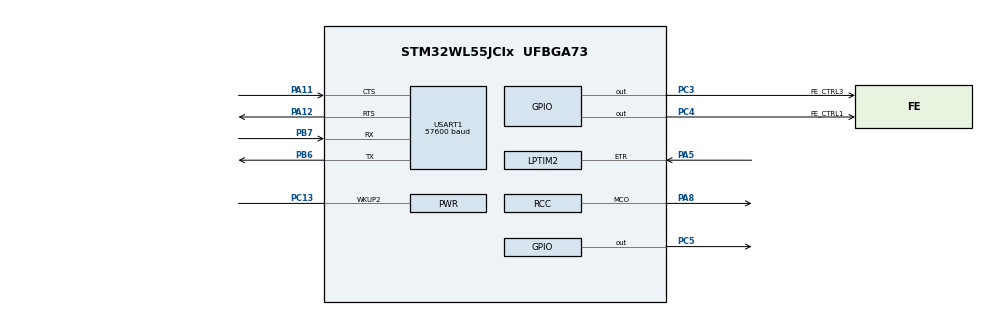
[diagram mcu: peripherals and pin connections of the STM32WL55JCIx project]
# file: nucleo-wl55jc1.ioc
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AES.KeySize=CRYP_KEYSIZE_128B
AES.pKey=DA123456 BE13579B FF3CC201 0F66CAED
Dma.MEMTOMEM.2.Channel_PRIV_NPRIV=DMA_CHANNEL_NPRIV_DISABLE
Dma.MEMTOMEM.2.Direction=DMA_MEMORY_TO_MEMORY
Dma.MEMTOMEM.2.EventEnable=DISABLE
Dma.MEMTOMEM.2.Instance=DMA1_Channel1
Dma.MEMTOMEM.2.MemDataAlignment=DMA_MDATAALIGN_BYTE
Dma.MEMTOMEM.2.MemInc=DMA_MINC_ENABLE
Dma.MEMTOMEM.2.Mode=DMA_NORMAL
Dma.MEMTOMEM.2.PeriphDataAlignment=DMA_PDATAALIGN_BYTE
Dma.MEMTOMEM.2.PeriphInc=DMA_PINC_ENABLE
Dma.MEMTOMEM.2.Polarity=HAL_DMAMUX_REQ_GEN_RISING
Dma.MEMTOMEM.2.Priority=DMA_PRIORITY_MEDIUM
Dma.MEMTOMEM.2.RequestNumber=1
Dma.MEMTOMEM.2.SignalID=NONE
Dma.MEMTOMEM.2.SyncEnable=DISABLE
Dma.MEMTOMEM.2.SyncPolarity=HAL_DMAMUX_SYNC_NO_EVENT
Dma.MEMTOMEM.2.SyncRequestNumber=1
Dma.MEMTOMEM.2.SyncSignalID=NONE
Dma.MEMTOMEM.3.Channel_PRIV_NPRIV=DMA_CHANNEL_NPRIV_DISABLE
Dma.MEMTOMEM.3.Direction=DMA_MEMORY_TO_MEMORY
Dma.MEMTOMEM.3.EventEnable=DISABLE
Dma.MEMTOMEM.3.Instance=DMA1_Channel2
Dma.MEMTOMEM.3.MemDataAlignment=DMA_MDATAALIGN_BYTE
Dma.MEMTOMEM.3.MemInc=DMA_MINC_ENABLE
Dma.MEMTOMEM.3.Mode=DMA_NORMAL
Dma.MEMTOMEM.3.PeriphDataAlignment=DMA_PDATAALIGN_BYTE
Dma.MEMTOMEM.3.PeriphInc=DMA_PINC_ENABLE
Dma.MEMTOMEM.3.Polarity=HAL_DMAMUX_REQ_GEN_RISING
Dma.MEMTOMEM.3.Priority=DMA_PRIORITY_MEDIUM
Dma.MEMTOMEM.3.RequestNumber=1
Dma.MEMTOMEM.3.SignalID=NONE
Dma.MEMTOMEM.3.SyncEnable=DISABLE
Dma.MEMTOMEM.3.SyncPolarity=HAL_DMAMUX_SYNC_NO_EVENT
Dma.MEMTOMEM.3.SyncRequestNumber=1
Dma.MEMTOMEM.3.SyncSignalID=NONE
Dma.MEMTOMEM.4.Channel_PRIV_NPRIV=DMA_CHANNEL_NPRIV_DISABLE
Dma.MEMTOMEM.4.Direction=DMA_MEMORY_TO_MEMORY
Dma.MEMTOMEM.4.EventEnable=DISABLE
Dma.MEMTOMEM.4.Instance=DMA1_Channel3
Dma.MEMTOMEM.4.MemDataAlignment=DMA_MDATAALIGN_BYTE
Dma.MEMTOMEM.4.MemInc=DMA_MINC_ENABLE
Dma.MEMTOMEM.4.Mode=DMA_NORMAL
Dma.MEMTOMEM.4.PeriphDataAlignment=DMA_PDATAALIGN_BYTE
Dma.MEMTOMEM.4.PeriphInc=DMA_PINC_ENABLE
Dma.MEMTOMEM.4.Polarity=HAL_DMAMUX_REQ_GEN_RISING
Dma.MEMTOMEM.4.Priority=DMA_PRIORITY_LOW
Dma.MEMTOMEM.4.RequestNumber=1
Dma.MEMTOMEM.4.SignalID=NONE
Dma.MEMTOMEM.4.SyncEnable=DISABLE
Dma.MEMTOMEM.4.SyncPolarity=HAL_DMAMUX_SYNC_NO_EVENT
Dma.MEMTOMEM.4.SyncRequestNumber=1
Dma.MEMTOMEM.4.SyncSignalID=NONE
Dma.MEMTOMEM.5.Channel_PRIV_NPRIV=DMA_CHANNEL_NPRIV_DISABLE
Dma.MEMTOMEM.5.Direction=DMA_MEMORY_TO_MEMORY
Dma.MEMTOMEM.5.EventEnable=DISABLE
Dma.MEMTOMEM.5.Instance=DMA1_Channel4
Dma.MEMTOMEM.5.MemDataAlignment=DMA_MDATAALIGN_BYTE
Dma.MEMTOMEM.5.MemInc=DMA_MINC_ENABLE
Dma.MEMTOMEM.5.Mode=DMA_NORMAL
Dma.MEMTOMEM.5.PeriphDataAlignment=DMA_PDATAALIGN_BYTE
Dma.MEMTOMEM.5.PeriphInc=DMA_PINC_ENABLE
Dma.MEMTOMEM.5.Polarity=HAL_DMAMUX_REQ_GEN_RISING
Dma.MEMTOMEM.5.Priority=DMA_PRIORITY_LOW
Dma.MEMTOMEM.5.RequestNumber=1
Dma.MEMTOMEM.5.SignalID=NONE
Dma.MEMTOMEM.5.SyncEnable=DISABLE
Dma.MEMTOMEM.5.SyncPolarity=HAL_DMAMUX_SYNC_NO_EVENT
Dma.MEMTOMEM.5.SyncRequestNumber=1
Dma.MEMTOMEM.5.SyncSignalID=NONE
Dma.Request0=USART1_RX
Dma.Request1=USART1_TX
Dma.Request2=MEMTOMEM
Dma.Request3=MEMTOMEM
Dma.Request4=MEMTOMEM
Dma.Request5=MEMTOMEM
Dma.USART1_RX.0.Channel_PRIV_NPRIV=DMA_CHANNEL_NPRIV_DISABLE
Dma.USART1_RX.0.Direction=DMA_PERIPH_TO_MEMORY
Dma.USART1_RX.0.EventEnable=ENABLE
Dma.USART1_RX.0.Instance=DMA1_Channel5
Dma.USART1_RX.0.MemDataAlignment=DMA_MDATAALIGN_BYTE
Dma.USART1_RX.0.MemInc=DMA_MINC_ENABLE
Dma.USART1_RX.0.Mode=DMA_NORMAL
Dma.USART1_RX.0.PeriphDataAlignment=DMA_PDATAALIGN_BYTE
Dma.USART1_RX.0.PeriphInc=DMA_PINC_DISABLE
Dma.USART1_RX.0.Polarity=HAL_DMAMUX_REQ_GEN_RISING
Dma.USART1_RX.0.Priority=DMA_PRIORITY_LOW
Dma.USART1_RX.0.RequestNumber=1
Dma.USART1_RX.0.SignalID=NONE
Dma.USART1_RX.0.SyncEnable=DISABLE
Dma.USART1_RX.0.SyncPolarity=HAL_DMAMUX_SYNC_NO_EVENT
Dma.USART1_RX.0.SyncRequestNumber=1
Dma.USART1_RX.0.SyncSignalID=NONE
Dma.USART1_TX.1.Channel_PRIV_NPRIV=DMA_CHANNEL_NPRIV_DISABLE
Dma.USART1_TX.1.Direction=DMA_MEMORY_TO_PERIPH
Dma.USART1_TX.1.EventEnable=ENABLE
Dma.USART1_TX.1.Instance=DMA1_Channel6
Dma.USART1_TX.1.MemDataAlignment=DMA_MDATAALIGN_BYTE
Dma.USART1_TX.1.MemInc=DMA_MINC_ENABLE
Dma.USART1_TX.1.Mode=DMA_NORMAL
Dma.USART1_TX.1.PeriphDataAlignment=DMA_PDATAALIGN_BYTE
Dma.USART1_TX.1.PeriphInc=DMA_PINC_DISABLE
Dma.USART1_TX.1.Polarity=HAL_DMAMUX_REQ_GEN_RISING
Dma.USART1_TX.1.Priority=DMA_PRIORITY_LOW
Dma.USART1_TX.1.RequestNumber=1
Dma.USART1_TX.1.SignalID=NONE
Dma.USART1_TX.1.SyncEnable=DISABLE
Dma.USART1_TX.1.SyncPolarity=HAL_DMAMUX_SYNC_NO_EVENT
Dma.USART1_TX.1.SyncRequestNumber=1
Dma.USART1_TX.1.SyncSignalID=NONE
Mcu.Family=STM32WL
Mcu.Name=STM32WL55JCIx
Mcu.Package=UFBGA73
NUCLEO-WL55JC1.BUTTON=1
NUCLEO-WL55JC1.BUTTON2=1
NUCLEO-WL55JC1.BUTTON3=1
NUCLEO-WL55JC1.LD1=true
NUCLEO-WL55JC1.LD2=true
NUCLEO-WL55JC1.LD3=true
NUCLEO-WL55JC1.VCP=true
NVIC.DMA1_Channel5_IRQn=true\:0\:0\:false\:false\:true\:false\:true\:true
NVIC.DMA1_Channel6_IRQn=true\:0\:0\:false\:false\:true\:false\:true\:true
NVIC.DMAMUX1_OVR_IRQn=true\:0\:0\:false\:false\:true\:false\:true\:true
NVIC.EXTI0_IRQn=true\:0\:0\:false\:false\:true\:false\:true\:true
NVIC.EXTI1_IRQn=true\:0\:0\:false\:false\:true\:false\:true\:true
NVIC.EXTI9_5_IRQn=true\:0\:0\:false\:false\:true\:false\:true\:true
NVIC.LPTIM1_IRQn=true\:0\:0\:false\:false\:true\:true\:true\:true
NVIC.PriorityGroup=NVIC_PRIORITYGROUP_4
NVIC.SUBGHZ_Radio_IRQn=true\:0\:0\:false\:false\:true\:true\:true\:true
NVIC.USART1_IRQn=true\:0\:0\:false\:false\:true\:true\:true\:true
PA11.Mode=CTS_RTS
PA11.Signal=USART1_CTS
PA12.Mode=CTS_RTS
PA12.Signal=USART1_RTS
PA2.Signal=USART2_TX
PA3.Signal=USART2_RX
PA5.Mode=ExternalTrigger
PA5.Signal=LPTIM2_ETR
PA8.Mode=Clock-out
PA8.Signal=RCC_MCO
PB3.Mode=RF-DTB1
PB3.Signal=DEBUG_RF-DTB1
PB6.Mode=Asynchronous
PB6.Signal=USART1_TX
PB7.Mode=Asynchronous
PB7.Signal=USART1_RX
PC13.Mode=WakeUp1
PC13.Signal=PWR_WKUP2
PC14-OSC32_IN.GPIO_Label=RCC_OSC32_IN
PC14-OSC32_IN.Signal=RCC_OSC32_IN
PC15-OSC32_OUT.GPIO_Label=RCC_OSC32_OUT
PC15-OSC32_OUT.Signal=RCC_OSC32_OUT
PC3.GPIO_Label=FE_CTRL3
PC3.GPIO_Speed=GPIO_SPEED_FREQ_VERY_HIGH
PC3.Signal=GPIO_Output
PC4.GPIO_Label=FE_CTRL1
PC4.GPIO_Speed=GPIO_SPEED_FREQ_VERY_HIGH
PC4.Signal=GPIO_Output
PC5.Signal=GPIO_Output
ProjectManager.HeapSize=0x200
ProjectManager.StackSize=0x400
ProjectManager.TargetToolchain=CMake
RCC.AHBFreq_Value=48000000
RCC.APB1CLKDivider=RCC_HCLK_DIV2
RCC.APB1Freq_Value=24000000
RCC.APB1TimFreq_Value=48000000
RCC.APB2Freq_Value=48000000
RCC.APB2TimFreq_Value=48000000
RCC.APB3Freq_Value=48000000
RCC.CortexFreq_Value=48000000
RCC.HCLKFreq_Value=48000000
RCC.HSE_VALUE=32000000
RCC.HSI_VALUE=16000000
RCC.LPTIM2CLockSelection=RCC_LPTIM2CLKSOURCE_HSI
RCC.LSE_VALUE=32768
RCC.MSIClockRange=RCC_MSIRANGE_11
RCC.PLLN=20
RCC.SYSCLKFreq_VALUE=48000000
RCC.USART1CLockSelection=RCC_USART1CLKSOURCE_HSI
RCC.VCOOutputFreq_Value=960000000
SUBGHZ_PHY.Activate_RADIO_BOARD_INTERFACE=UserBoard
USART1.BaudRate=57600
USART1.VirtualMode-Asynchronous=VM_ASYNC
VP_ADV_TRACE_VS_ADV_TRACE.Mode=ADV_TRACE_Enabled
VP_AES_VS_AES.Mode=AES_Activate
VP_LPTIM1_VS_LPTIM_counterModeInternalClock.Mode=Counts__internal_clock_event_00
VP_LPTIM2_VS_LPTIM_counterModeInternalClock.Mode=Counts__internal_clock_event_00
VP_MISC_VS_MISC.Mode=MISC_Enabled
VP_NUCLEO-WL55JC1_VS_BSP_COMMON.Mode=COMMON
VP_RNG_VS_RNG.Mode=RNG_Activate
VP_SEQUENCER_M4_VS_SEQUENCER.Mode=SEQUENCER_Enabled
VP_SUBGHZ_PHY_VS_SubGhzPhy.Mode=SubGhzPhy_Enabled
VP_SUBGHZ_VS_SUBGHZ.Mode=SUBGHZ_Activate
VP_TIMER_VS_TIMER.Mode=TIMER_Enabled
VP_TINY_LPM_VS_TINY_LPM.Mode=TINY_LPM_Enabled
board=NUCLEO-WL55JC1

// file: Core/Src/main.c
/* USER CODE BEGIN Header */
/**
  ******************************************************************************
  * @file           : main.c
  * @brief          : Main program body
  ******************************************************************************
  * @attention
  *
  * Copyright (c) 2024 STMicroelectronics.
  * All rights reserved.
  *
  * This software is licensed under terms that can be found in the LICENSE file
  * in the root directory of this software component.
  * If no LICENSE file comes with this software, it is provided AS-IS.
  *
  ******************************************************************************
  */
/* USER CODE END Header */
#include "main.h"
#include "aes.h"
#include "dma.h"
#include "lptim.h"
#include "rng.h"
#include "app_subghz_phy.h"
#include "usart.h"
#include "gpio.h"

COM_InitTypeDef BspCOMInit;

void SystemClock_Config(void);

int main(void)
{

  /* MCU Configuration--------------------------------------------------------*/

  /* Reset of all peripherals, Initializes the Flash interface and the Systick. */
  HAL_Init();

  /* Configure the system clock */
  SystemClock_Config();

  /* Initialize all configured peripherals */
  MX_GPIO_Init();
  MX_DMA_Init();
  MX_AES_Init();
  MX_RNG_Init();
  MX_USART1_UART_Init();
  MX_SubGHz_Phy_Init();
  MX_LPTIM1_Init();
  MX_LPTIM2_Init();

  /* Initialize leds */
  BSP_LED_Init(LED_BLUE);
  BSP_LED_Init(LED_GREEN);
  BSP_LED_Init(LED_RED);

  /* Initialize USER push-button, will be used to trigger an interrupt each time it's pressed.*/
  BSP_PB_Init(BUTTON_SW1, BUTTON_MODE_EXTI);
  BSP_PB_Init(BUTTON_SW2, BUTTON_MODE_EXTI);
  BSP_PB_Init(BUTTON_SW3, BUTTON_MODE_EXTI);

  /* Initialize COM1 port (115200, 8 bits (7-bit data + 1 stop bit), no parity */
  BspCOMInit.BaudRate   = 115200;
  BspCOMInit.WordLength = COM_WORDLENGTH_8B;
  BspCOMInit.StopBits   = COM_STOPBITS_1;
  BspCOMInit.Parity     = COM_PARITY_NONE;
  BspCOMInit.HwFlowCtl  = COM_HWCONTROL_NONE;
  if (BSP_COM_Init(COM1, &BspCOMInit) != BSP_ERROR_NONE)
  {
    Error_Handler();
  }

  // custom main
  st_main();
}

void SystemClock_Config(void)
{
  RCC_OscInitTypeDef RCC_OscInitStruct = {0};
  RCC_ClkInitTypeDef RCC_ClkInitStruct = {0};

  /** Configure the main internal regulator output voltage
  */
  __HAL_PWR_VOLTAGESCALING_CONFIG(PWR_REGULATOR_VOLTAGE_SCALE1);

  /** Initializes the CPU, AHB and APB buses clocks
  */
  RCC_OscInitStruct.OscillatorType = RCC_OSCILLATORTYPE_HSI|RCC_OSCILLATORTYPE_LSI
                              |RCC_OSCILLATORTYPE_MSI;
  RCC_OscInitStruct.HSIState = RCC_HSI_ON;
  RCC_OscInitStruct.MSIState = RCC_MSI_ON;
  RCC_OscInitStruct.HSICalibrationValue = RCC_HSICALIBRATION_DEFAULT;
  RCC_OscInitStruct.MSICalibrationValue = RCC_MSICALIBRATION_DEFAULT;
  RCC_OscInitStruct.MSIClockRange = RCC_MSIRANGE_11;
  RCC_OscInitStruct.LSIDiv = RCC_LSI_DIV1;
  RCC_OscInitStruct.LSIState = RCC_LSI_ON;
  RCC_OscInitStruct.PLL.PLLState = RCC_PLL_ON;
  RCC_OscInitStruct.PLL.PLLSource = RCC_PLLSOURCE_MSI;
  RCC_OscInitStruct.PLL.PLLM = RCC_PLLM_DIV4;
  RCC_OscInitStruct.PLL.PLLN = 24;
  RCC_OscInitStruct.PLL.PLLP = RCC_PLLP_DIV2;
  RCC_OscInitStruct.PLL.PLLR = RCC_PLLR_DIV6;
  RCC_OscInitStruct.PLL.PLLQ = RCC_PLLQ_DIV2;
  if (HAL_RCC_OscConfig(&RCC_OscInitStruct) != HAL_OK)
  {
    Error_Handler();
  }

  /** Configure the SYSCLKSource, HCLK, PCLK1 and PCLK2 clocks dividers
  */
  RCC_ClkInitStruct.ClockType = RCC_CLOCKTYPE_HCLK3|RCC_CLOCKTYPE_HCLK
                              |RCC_CLOCKTYPE_SYSCLK|RCC_CLOCKTYPE_PCLK1
                              |RCC_CLOCKTYPE_PCLK2;
  RCC_ClkInitStruct.SYSCLKSource = RCC_SYSCLKSOURCE_PLLCLK;
  RCC_ClkInitStruct.AHBCLKDivider = RCC_SYSCLK_DIV1;
  RCC_ClkInitStruct.APB1CLKDivider = RCC_HCLK_DIV1;
  RCC_ClkInitStruct.APB2CLKDivider = RCC_HCLK_DIV1;
  RCC_ClkInitStruct.AHBCLK3Divider = RCC_SYSCLK_DIV1;

  if (HAL_RCC_ClockConfig(&RCC_ClkInitStruct, FLASH_LATENCY_2) != HAL_OK)
  {
    Error_Handler();
  }
}
